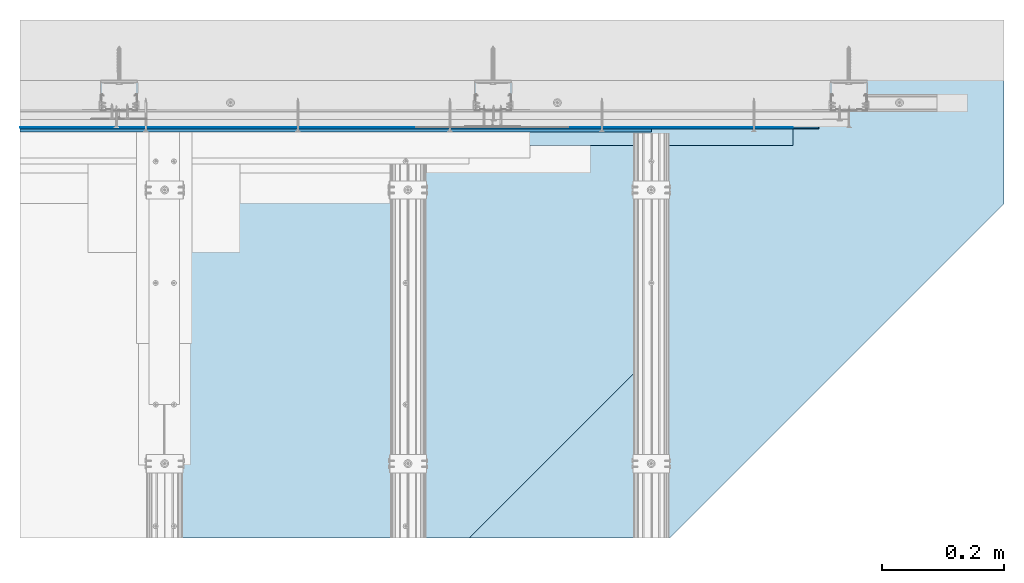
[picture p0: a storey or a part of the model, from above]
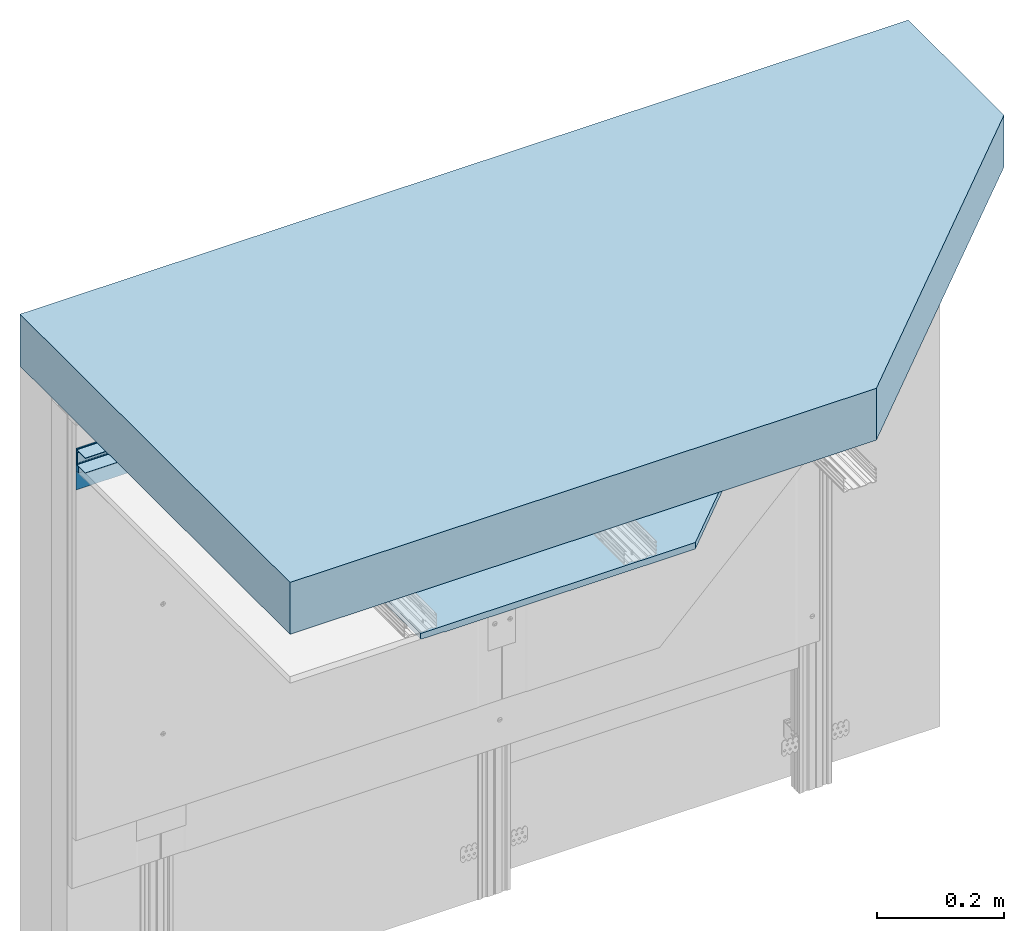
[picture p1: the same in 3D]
Properties of the parts of a building model (IFC2X3)

# File
Description: ViewDefinition [CoordinationView]
Time: 2022-01-05T16:14:12
Made in: SketchUp Pro 2015

# IfcProject, Default Project
Description: Description of Default Project

# IfcSite, Default Site
Description: Description of Default Site; RefLatitude: 24, 28, 0; RefLongitude: 54, 25, 0; RefElevation: 10 mm

# IfcBuilding, Default Building
Description: Description of Default Building

# IfcBuildingStorey, Default Building Storey
In: Default Building
Description: Description of Default Building Storey; Elevation: 0 mm

# IfcSlab (91)
In: Default Building Storey
Description: Description of Object
PredefinedType - IfcSlabTypeEnum: floor
Name
STROP
Taśma uszczelniająca piankowa RIGIPS
3 x Profil RIGIPS CD60 ULTRASTIL®
Profil RIGIPS UD30 ULTRASTIL®
5 x Wkręt RIGIPS TN 55
2 x Dedykowana masa szpachlowa Rigips - wykończeniowa
5 x Dedykowana masa szpachlowa Rigips - konstrukcyjna
2 x Płyta gipsowo-kartonowa RIGIPS PRO (4PRO™)
2 x Taśma spoinowa RIGIPS
30 x Wkręt RIGIPS "pchełka" 3,9 x 11 mm
6 x Uchwyt RIGIPS ES 75 do profila CD60
12 x Stalowe elementy mocujące
6 x Taśma uszczelniająca piankowa RIGIPS szer.30mm
14 x Wkręt RIGIPS TN 25
Taśma samoprzylepna RIGIPS (ślizgowa)

# IfcWall (88)
In: Default Building Storey
Description: Description of Object
Name
Taśma spoinowa RIGIPS
8 x Wkręt RIGIPS TN 25
11 x Wkręt RIGIPS TN 35
4 x Płyta gipsowo-kartonowa RIGIPS PRO (4PRO™)
3 x Dedykowana masa szpachlowa Rigips - konstrukcyjna
Dedykowana masa szpachlowa Rigips - wykończeniowa
ŚCIANA
6 x Wypełnienie wełny mineralnej szklanej lub skalnej ISOVER
18 x Kołek rozporowy min. fi 6
Taśma uszczelniająca piankowa RIGIPS
3 x Profil RIGIPS CD60 ULTRASTIL®
Profil RIGIPS UD30 ULTRASTIL®
18 x Wkręt RIGIPS "pchełka" 3,9 x 11 mm
6 x Taśma uszczelniająca piankowa RIGIPS szer.30mm
6 x Uchwyt RIGIPS ES 75 do profila CD60
